VERSION 5.7 ;
  NOWIREEXTENSIONATPIN ON ;
  DIVIDERCHAR "/" ;
  BUSBITCHARS "[]" ;
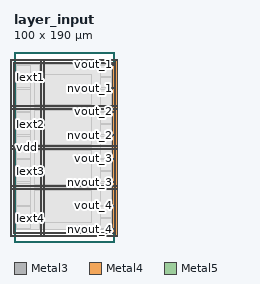
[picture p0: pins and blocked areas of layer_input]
MACRO layer_input
  CLASS BLOCK ;
  FOREIGN layer_input ;
  ORIGIN 0.000 0.000 ;
  SIZE 100.000 BY 190.000 ;
  PIN Iext1
    DIRECTION INPUT ;
    USE SIGNAL ;
    ANTENNAGATEAREA 0.280000 ;
    ANTENNADIFFAREA 1.380000 ;
    PORT
      LAYER Metal3 ;
        RECT 0.000 164.500 2.500 165.340 ;
    END
  END Iext1
  PIN Iext2
    DIRECTION INPUT ;
    USE SIGNAL ;
    ANTENNAGATEAREA 0.280000 ;
    ANTENNADIFFAREA 1.380000 ;
    PORT
      LAYER Metal3 ;
        RECT 0.000 117.460 2.500 118.300 ;
    END
  END Iext2
  PIN Iext3
    DIRECTION INPUT ;
    USE SIGNAL ;
    ANTENNAGATEAREA 0.280000 ;
    ANTENNADIFFAREA 1.380000 ;
    PORT
      LAYER Metal3 ;
        RECT 0.000 70.420 2.500 71.260 ;
    END
  END Iext3
  PIN Iext4
    DIRECTION INPUT ;
    USE SIGNAL ;
    ANTENNAGATEAREA 0.280000 ;
    ANTENNADIFFAREA 1.380000 ;
    PORT
      LAYER Metal3 ;
        RECT 0.000 23.380 2.500 24.220 ;
    END
  END Iext4
  PIN nvout_1
    DIRECTION OUTPUT ;
    USE SIGNAL ;
    ANTENNAGATEAREA 0.560000 ;
    ANTENNADIFFAREA 0.750000 ;
    PORT
      LAYER Metal3 ;
        RECT 97.500 153.300 100.000 154.140 ;
    END
  END nvout_1
  PIN nvout_2
    DIRECTION OUTPUT ;
    USE SIGNAL ;
    ANTENNAGATEAREA 0.560000 ;
    ANTENNADIFFAREA 0.750000 ;
    PORT
      LAYER Metal3 ;
        RECT 97.500 106.260 100.000 107.100 ;
    END
  END nvout_2
  PIN nvout_3
    DIRECTION OUTPUT ;
    USE SIGNAL ;
    ANTENNAGATEAREA 0.560000 ;
    ANTENNADIFFAREA 0.750000 ;
    PORT
      LAYER Metal3 ;
        RECT 97.500 59.220 100.000 60.060 ;
    END
  END nvout_3
  PIN nvout_4
    DIRECTION OUTPUT ;
    USE SIGNAL ;
    ANTENNAGATEAREA 0.560000 ;
    ANTENNADIFFAREA 0.750000 ;
    PORT
      LAYER Metal3 ;
        RECT 97.500 12.180 100.000 13.020 ;
    END
  END nvout_4
  PIN vdd
    DIRECTION INOUT ;
    USE POWER ;
    PORT
      LAYER Metal4 ;
        RECT -0.780 8.180 0.720 179.980 ;
    END
    PORT
      LAYER Metal4 ;
        RECT 98.960 8.180 100.460 179.980 ;
    END
    PORT
      LAYER Metal5 ;
        RECT -0.780 8.180 100.460 9.680 ;
    END
    PORT
      LAYER Metal5 ;
        RECT -0.780 178.480 100.460 179.980 ;
    END
    PORT
      LAYER Metal4 ;
        RECT 26.120 5.180 27.320 182.980 ;
    END
    PORT
      LAYER Metal5 ;
        RECT -3.780 52.080 103.460 53.280 ;
    END
    PORT
      LAYER Metal5 ;
        RECT -3.780 92.080 103.460 93.280 ;
    END
    PORT
      LAYER Metal5 ;
        RECT -3.780 132.080 103.460 133.280 ;
    END
  END vdd
  PIN vout_1
    DIRECTION OUTPUT ;
    USE SIGNAL ;
    ANTENNADIFFAREA 0.750000 ;
    PORT
      LAYER Metal3 ;
        RECT 97.500 176.820 100.000 177.660 ;
    END
  END vout_1
  PIN vout_2
    DIRECTION OUTPUT ;
    USE SIGNAL ;
    ANTENNADIFFAREA 0.750000 ;
    PORT
      LAYER Metal3 ;
        RECT 97.500 129.780 100.000 130.620 ;
    END
  END vout_2
  PIN vout_3
    DIRECTION OUTPUT ;
    USE SIGNAL ;
    ANTENNADIFFAREA 0.750000 ;
    PORT
      LAYER Metal3 ;
        RECT 97.500 82.740 100.000 83.580 ;
    END
  END vout_3
  PIN vout_4
    DIRECTION OUTPUT ;
    USE SIGNAL ;
    ANTENNADIFFAREA 0.750000 ;
    PORT
      LAYER Metal3 ;
        RECT 97.500 35.700 100.000 36.540 ;
    END
  END vout_4
  PIN vss
    DIRECTION INOUT ;
    USE GROUND ;
    PORT
      LAYER Metal4 ;
        RECT -3.780 5.180 -2.280 182.980 ;
    END
    PORT
      LAYER Metal4 ;
        RECT 101.960 5.180 103.460 182.980 ;
    END
    PORT
      LAYER Metal5 ;
        RECT -3.780 5.180 103.460 6.680 ;
    END
    PORT
      LAYER Metal5 ;
        RECT -3.780 181.480 103.460 182.980 ;
    END
    PORT
      LAYER Metal4 ;
        RECT 29.320 5.180 30.520 182.980 ;
    END
    PORT
      LAYER Metal5 ;
        RECT -3.780 55.280 103.460 56.480 ;
    END
    PORT
      LAYER Metal5 ;
        RECT -3.780 95.280 103.460 96.480 ;
    END
    PORT
      LAYER Metal5 ;
        RECT -3.780 135.280 103.460 136.480 ;
    END
  END vss
  OBS
      LAYER Nwell ;
        RECT 22.000 23.300 75.860 163.890 ;
      LAYER Metal1 ;
        RECT 22.190 23.510 75.630 163.680 ;
      LAYER Metal2 ;
        RECT 20.650 20.250 76.170 167.640 ;
      LAYER Metal3 ;
        RECT 2.500 176.520 97.200 177.380 ;
        RECT 2.500 165.640 97.500 176.520 ;
        RECT 2.800 164.200 97.500 165.640 ;
        RECT 2.500 154.440 97.500 164.200 ;
        RECT 2.500 153.000 97.200 154.440 ;
        RECT 2.500 130.920 97.500 153.000 ;
        RECT 2.500 129.480 97.200 130.920 ;
        RECT 2.500 118.600 97.500 129.480 ;
        RECT 2.800 117.160 97.500 118.600 ;
        RECT 2.500 107.400 97.500 117.160 ;
        RECT 2.500 105.960 97.200 107.400 ;
        RECT 2.500 83.880 97.500 105.960 ;
        RECT 2.500 82.440 97.200 83.880 ;
        RECT 2.500 71.560 97.500 82.440 ;
        RECT 2.800 70.120 97.500 71.560 ;
        RECT 2.500 60.360 97.500 70.120 ;
        RECT 2.500 58.920 97.200 60.360 ;
        RECT 2.500 36.840 97.500 58.920 ;
        RECT 2.500 35.400 97.200 36.840 ;
        RECT 2.500 24.520 97.500 35.400 ;
        RECT 2.800 23.080 97.500 24.520 ;
        RECT 2.500 13.320 97.500 23.080 ;
        RECT 2.500 12.460 97.200 13.320 ;
      LAYER Metal4 ;
        RECT 16.940 12.410 25.820 177.430 ;
        RECT 27.620 12.410 29.020 177.430 ;
        RECT 30.820 12.410 86.660 177.430 ;
      LAYER Metal5 ;
        RECT 20.000 137.080 77.860 167.890 ;
        RECT 20.000 133.880 77.860 134.680 ;
        RECT 20.000 97.080 77.860 131.480 ;
        RECT 20.000 93.880 77.860 94.680 ;
        RECT 20.000 57.080 77.860 91.480 ;
        RECT 20.000 53.880 77.860 54.680 ;
        RECT 20.000 20.000 77.860 51.480 ;
  END
END layer_input
END LIBRARY

